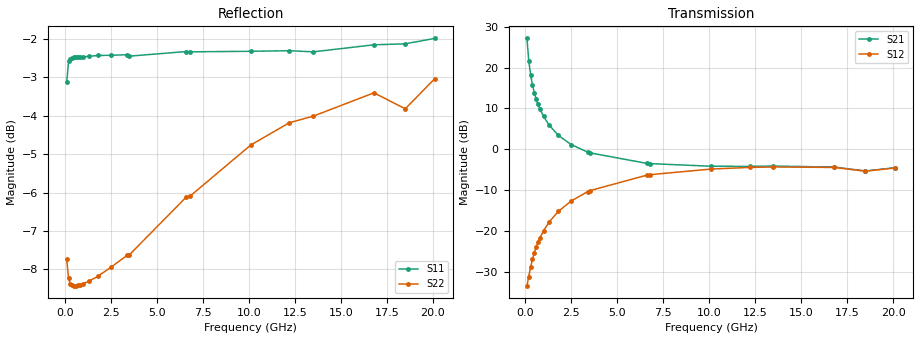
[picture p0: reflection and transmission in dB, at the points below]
!  Infineon Technologies AG
! BFR380L3 , PF131585-7, No.6, Th 09.10.01, soldered on pcb-board, measured with PP GSG850
!  Vce=0.75 V,  Ic=80.0 mA
! Common Emitter S-Parameters:  15. November 2001
#  GHz  S  MA  R  50
! f  S11  S21  S12  S22
! GHz  Mag  Ang  Mag  Ang  Mag  Ang  Mag  Ang
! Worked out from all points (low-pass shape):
!   201 points, 100 MHz to 20.1 GHz, reference 50 ohm
!   highest |S21| = 27.18 dB at 100 MHz (marker M1); lowest = -5.3 dB at 18.5 GHz (marker M2)
!   |S21| within 3 dB of the highest: start of sweep to 154.2 MHz
!   lowest |S11| = -3.1 dB at 100 MHz (marker M3), VSWR 5.60, Z = 9.39 - j11.3 ohm
!   |S11| at or under -10 dB: nowhere
!   |S22| runs from -8.4 to -3.0 dB; largest |S21 - S12| = 23
!   S11 on the Smith chart (normalised r, x): 100 MHz: 0.19, -0.23; 1 GHz: 0.14, +0.11; 3.4 GHz: 0.17, +0.44; 6.6 GHz: 0.24, +0.87; 12.2 GHz: 0.48, +1.58; 20.1 GHz: 1.02, +2.66
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0.1  0.6972 -153.7  22.86 110.6  0.02129 48.7  0.4105 -126.5
0.2  0.7426 -168.7  12.09 97.7  0.02758 54.3  0.3874 -152.4
0.3  0.7478 -174.9  8.169 92.2  0.03612 60.5  0.381 -162.6
0.4  0.749 -178.8  6.164 88.4  0.04491 64.2  0.3795 -168.1
0.5  0.7521 178.1  4.952 85.4  0.05395 66.6  0.3792 -171.8
0.6  0.7517 175.6  4.141 82.8  0.06319 67.8  0.3791 -174.5
0.7  0.7516 173.5  3.567 80.4  0.07232 68.7  0.3798 -176.7
0.8  0.7528 171.4  3.134 78.2  0.08173 69.1  0.3799 -178.5
1  0.7524 167.6  2.535 74.0  0.1002 69.1  0.3814 178.5
1.3  0.7539 162.3  1.984 68.3  0.1278 67.8  0.3841 174.8
1.8  0.7557 154.4  1.485 59.6  0.1728 64.6  0.39 169.7
2.5  0.7562 144.0  1.143 48.9  0.2319 59.1  0.4006 163.2
3.4  0.7575 131.5  0.9227 37.2  0.3024 51.3  0.4155 155.1
3.5  0.7542 130.2  0.9058 36.2  0.3103 50.5  0.4157 154.5
6.6  0.7647 96.3  0.6726 11.0  0.4802 25.3  0.4945 128.2
6.8  0.764 94.4  0.667 9.6  0.4884 23.7  0.4957 126.4
10.1  0.7653 71.3  0.6195 -6.1  0.5719 2.3  0.5778 103.5
12.2  0.7666 61.3  0.6174 -15.1  0.5991 -9.4  0.6178 90.0
13.5  0.764 55.8  0.6229 -20.8  0.6064 -16.4  0.6301 82.4
16.8  0.7803 45.0  0.6049 -32.4  0.5989 -30.1  0.6757 66.2
18.5  0.7826 43.3  0.542 -39.8  0.538 -37.8  0.6441 62.6
20.1  0.7955 36.8  0.5938 -43.5  0.59 -42.1  0.7049 53.0
